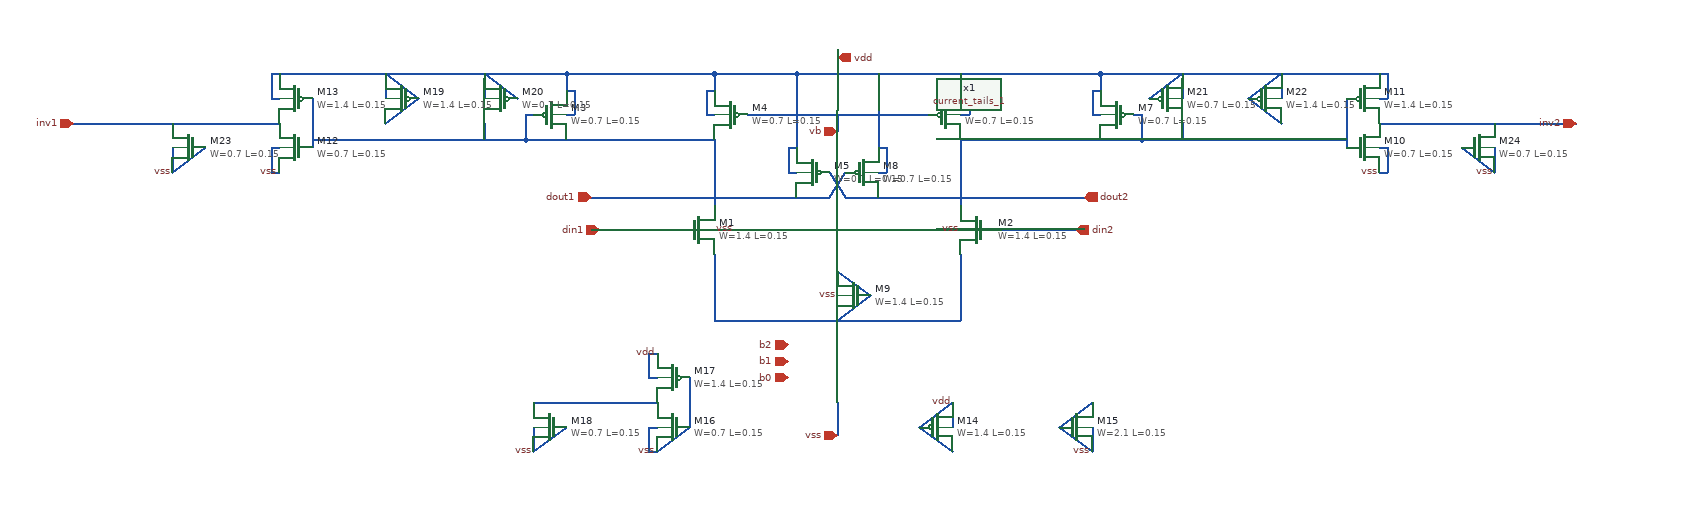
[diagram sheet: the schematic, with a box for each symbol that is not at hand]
v {xschem version=3.1.0 file_version=1.2
}
G {}
K {}
V {}
S {}
E {}
N 1120 -670 1120 -590 { lab=dout1}
N 890 -670 940 -670 { lab=dout1}
N 890 -700 890 -670 { lab=dout1}
N 890 -700 900 -700 { lab=dout1}
N 940 -750 940 -730 { lab=vdd}
N 1120 -750 1120 -730 { lab=vdd}
N 1140 -750 1220 -750 { lab=vdd}
N 1220 -750 1220 -660 { lab=vdd}
N 1210 -630 1220 -630 { lab=vdd}
N 1210 -660 1210 -630 { lab=vdd}
N 1210 -660 1220 -660 { lab=vdd}
N 1140 -600 1220 -600 { lab=dout1}
N 1420 -670 1420 -590 { lab=dout2}
N 1590 -670 1640 -670 { lab=dout2}
N 1640 -700 1640 -670 { lab=dout2}
N 1630 -700 1640 -700 { lab=dout2}
N 1590 -750 1590 -730 { lab=vdd}
N 1220 -750 1480 -750 { lab=vdd}
N 1420 -750 1420 -730 { lab=vdd}
N 1320 -600 1400 -600 { lab=dout2}
N 1320 -750 1320 -660 { lab=vdd}
N 1320 -630 1330 -630 { lab=vdd}
N 1330 -660 1330 -630 { lab=vdd}
N 1320 -660 1330 -660 { lab=vdd}
N 1110 -700 1120 -700 { lab=vdd}
N 1110 -730 1110 -700 { lab=vdd}
N 1110 -730 1120 -730 { lab=vdd}
N 1420 -700 1430 -700 { lab=vdd}
N 1430 -730 1430 -700 { lab=vdd}
N 1420 -730 1430 -730 { lab=vdd}
N 1580 -700 1590 -700 { lab=vdd}
N 1580 -730 1580 -700 { lab=vdd}
N 1580 -730 1590 -730 { lab=vdd}
N 940 -700 950 -700 { lab=vdd}
N 950 -730 950 -700 { lab=vdd}
N 940 -730 950 -730 { lab=vdd}
N 970 -560 1080 -560 { lab=din1}
N 1460 -560 1570 -560 { lab=din2}
N 1420 -600 1570 -600 { lab=dout2}
N 970 -600 1120 -600 { lab=dout1}
N 1180 -700 1360 -700 { lab=vb}
N 1270 -700 1270 -680 { lab=vb}
N 1270 -780 1270 -750 {
lab=vdd}
N 1570 -750 1590 -750 {
lab=vdd}
N 940 -750 970 -750 {
lab=vdd}
N 1400 -600 1420 -600 {
lab=dout2}
N 1360 -700 1380 -700 {
lab=vb}
N 1120 -600 1140 -600 {
lab=dout1}
N 1160 -700 1180 -700 {
lab=vb}
N 1120 -750 1140 -750 {
lab=vdd}
N 970 -750 1120 -750 {
lab=vdd}
N 1480 -750 1570 -750 {
lab=vdd}
N 1420 -670 1590 -670 {
lab=dout2}
N 940 -670 1120 -670 {
lab=dout1}
N 1220 -600 1260 -600 {
lab=dout1}
N 1260 -600 1280 -630 {
lab=dout1}
N 1260 -630 1280 -600 {
lab=dout2}
N 1280 -600 1320 -600 {
lab=dout2}
N 1120 -530 1120 -450 {
lab=#net1}
N 1120 -450 1420 -450 {
lab=#net1}
N 1420 -530 1420 -450 {
lab=#net1}
N 1270 -510 1310 -480 {
lab=#net1}
N 1270 -450 1310 -480 {
lab=#net1}
N 1930 -720 1940 -720 {
lab=vdd}
N 1940 -750 1940 -720 {
lab=vdd}
N 1930 -750 1940 -750 {
lab=vdd}
N 1930 -630 1940 -630 {
lab=vss}
N 1940 -660 1940 -630 {
lab=vss}
N 1930 -660 1940 -660 {
lab=vss}
N 580 -630 590 -630 {
lab=vss}
N 580 -660 580 -630 {
lab=vss}
N 580 -660 590 -660 {
lab=vss}
N 580 -720 590 -720 {
lab=vdd}
N 580 -750 580 -720 {
lab=vdd}
N 580 -750 590 -750 {
lab=vdd}
N 1890 -720 1890 -660 {
lab=dout2}
N 630 -720 630 -660 {
lab=dout1}
N 1370 -320 1410 -290 {
lab=vdd}
N 1370 -320 1410 -350 {
lab=vdd}
N 1410 -350 1410 -320 {
lab=vdd}
N 1540 -320 1580 -290 {
lab=vss}
N 1540 -320 1580 -350 {
lab=vss}
N 1580 -320 1580 -290 {
lab=vss}
N 1040 -290 1050 -290 {
lab=vss}
N 1040 -320 1040 -290 {
lab=vss}
N 1040 -320 1050 -320 {
lab=vss}
N 1040 -380 1050 -380 {
lab=vdd}
N 1040 -410 1040 -380 {
lab=vdd}
N 1040 -410 1050 -410 {
lab=vdd}
N 1090 -380 1090 -320 {
lab=vss}
N 1050 -290 1090 -320 {
lab=vss}
N 750 -670 890 -670 {
lab=dout1}
N 710 -750 940 -750 {
lab=vdd}
N 1590 -750 1820 -750 {
lab=vdd}
N 1640 -670 1780 -670 {
lab=dout2}
N 1690 -750 1690 -720 {
lab=vdd}
N 1650 -720 1690 -750 {
lab=vdd}
N 1690 -690 1690 -670 {
lab=dout2}
N 720 -750 720 -720 {
lab=vdd}
N 720 -750 760 -720 {
lab=vdd}
N 1930 -690 2030 -690 {
lab=inv1}
N 500 -690 590 -690 {
lab=inv1}
N 1780 -670 1890 -670 {
lab=dout2}
N 1770 -720 1810 -690 {
lab=vdd}
N 1770 -720 1810 -750 {
lab=vdd}
N 1810 -750 1810 -720 {
lab=vdd}
N 1820 -750 1930 -750 {
lab=vdd}
N 720 -690 760 -720 {
lab=vdd}
N 2030 -690 2170 -690 {
lab=inv1}
N 340 -690 500 -690 {
lab=inv1}
N 460 -630 500 -660 {
lab=vss}
N 460 -660 460 -630 {
lab=vss}
N 900 -350 1050 -350 {
lab=#net2}
N 900 -290 940 -320 {
lab=vss}
N 900 -320 900 -290 {
lab=vss}
N 630 -670 750 -670 {
lab=dout1}
N 590 -750 710 -750 {
lab=vdd}
N 840 -690 840 -670 {
lab=dout1}
N 840 -750 880 -720 {
lab=vdd}
N 840 -750 840 -720 {
lab=vdd}
N 2030 -660 2070 -630 {
lab=vss}
N 2070 -660 2070 -630 {
lab=vss}
N 1270 -350 1270 -310 {
lab=vss}
C {sky130_fd_pr/pfet_01v8.sym} 1240 -630 0 1 {name=M5
L=0.15
W=0.7
nf=1
mult=1
ad="'int((nf+1)/2) * W/nf * 0.29'" 
pd="'2*int((nf+1)/2) * (W/nf + 0.29)'"
as="'int((nf+2)/2) * W/nf * 0.29'" 
ps="'2*int((nf+2)/2) * (W/nf + 0.29)'"
nrd="'0.29 / W'" nrs="'0.29 / W'"
sa=0 sb=0 sd=0
model=pfet_01v8
spiceprefix=X
}
C {sky130_fd_pr/pfet_01v8.sym} 1300 -630 0 0 {name=M8
L=0.15
W=0.7
nf=1
mult=1
ad="'int((nf+1)/2) * W/nf * 0.29'" 
pd="'2*int((nf+1)/2) * (W/nf + 0.29)'"
as="'int((nf+2)/2) * W/nf * 0.29'" 
ps="'2*int((nf+2)/2) * (W/nf + 0.29)'"
nrd="'0.29 / W'" nrs="'0.29 / W'"
sa=0 sb=0 sd=0
model=pfet_01v8
spiceprefix=X
}
C {sky130_fd_pr/pfet_01v8.sym} 920 -700 0 0 {name=M3
L=0.15
W=0.7
nf=1
mult=1
ad="'int((nf+1)/2) * W/nf * 0.29'" 
pd="'2*int((nf+1)/2) * (W/nf + 0.29)'"
as="'int((nf+2)/2) * W/nf * 0.29'" 
ps="'2*int((nf+2)/2) * (W/nf + 0.29)'"
nrd="'0.29 / W'" nrs="'0.29 / W'"
sa=0 sb=0 sd=0
model=pfet_01v8
spiceprefix=X
}
C {sky130_fd_pr/pfet_01v8.sym} 1140 -700 0 1 {name=M4
L=0.15
W=0.7
nf=1
mult=1
ad="'int((nf+1)/2) * W/nf * 0.29'" 
pd="'2*int((nf+1)/2) * (W/nf + 0.29)'"
as="'int((nf+2)/2) * W/nf * 0.29'" 
ps="'2*int((nf+2)/2) * (W/nf + 0.29)'"
nrd="'0.29 / W'" nrs="'0.29 / W'"
sa=0 sb=0 sd=0
model=pfet_01v8
spiceprefix=X
}
C {sky130_fd_pr/pfet_01v8.sym} 1400 -700 0 0 {name=M6
L=0.15
W=0.7
nf=1
mult=1
ad="'int((nf+1)/2) * W/nf * 0.29'" 
pd="'2*int((nf+1)/2) * (W/nf + 0.29)'"
as="'int((nf+2)/2) * W/nf * 0.29'" 
ps="'2*int((nf+2)/2) * (W/nf + 0.29)'"
nrd="'0.29 / W'" nrs="'0.29 / W'"
sa=0 sb=0 sd=0
model=pfet_01v8
spiceprefix=X
}
C {sky130_fd_pr/pfet_01v8.sym} 1610 -700 0 1 {name=M7
L=0.15
W=0.7
nf=1
mult=1
ad="'int((nf+1)/2) * W/nf * 0.29'" 
pd="'2*int((nf+1)/2) * (W/nf + 0.29)'"
as="'int((nf+2)/2) * W/nf * 0.29'" 
ps="'2*int((nf+2)/2) * (W/nf + 0.29)'"
nrd="'0.29 / W'" nrs="'0.29 / W'"
sa=0 sb=0 sd=0
model=pfet_01v8
spiceprefix=X
}
C {devices/iopin.sym} 1270 -770 1 1 {name=p1 lab=vdd}
C {devices/iopin.sym} 1270 -310 1 0 {name=p2 lab=vss}
C {devices/iopin.sym} 1270 -680 1 0 {name=p3 lab=vb}
C {devices/iopin.sym} 980 -560 2 0 {name=p4 lab=din1}
C {devices/iopin.sym} 1560 -560 2 1 {name=p5 lab=din2}
C {devices/iopin.sym} 1570 -600 2 1 {name=p6 lab=dout2}
C {devices/iopin.sym} 970 -600 2 0 {name=p7 lab=dout1}
C {sky130_fd_pr/nfet_01v8_lvt.sym} 1100 -560 0 0 {name=M1
L=0.15
W=1.4
nf=2
mult=1
ad="'int((nf+1)/2) * W/nf * 0.29'" 
pd="'2*int((nf+1)/2) * (W/nf + 0.29)'"
as="'int((nf+2)/2) * W/nf * 0.29'" 
ps="'2*int((nf+2)/2) * (W/nf + 0.29)'"
nrd="'0.29 / W'" nrs="'0.29 / W'"
sa=0 sb=0 sd=0
model=nfet_01v8_lvt
spiceprefix=X
}
C {sky130_fd_pr/nfet_01v8_lvt.sym} 1440 -560 0 1 {name=M2
L=0.15
W=1.4
nf=2
mult=1
ad="'int((nf+1)/2) * W/nf * 0.29'" 
pd="'2*int((nf+1)/2) * (W/nf + 0.29)'"
as="'int((nf+2)/2) * W/nf * 0.29'" 
ps="'2*int((nf+2)/2) * (W/nf + 0.29)'"
nrd="'0.29 / W'" nrs="'0.29 / W'"
sa=0 sb=0 sd=0
model=nfet_01v8_lvt
spiceprefix=X
}
C {devices/iopin.sym} 1210 -420 2 0 {name=p8 lab=b2}
C {devices/iopin.sym} 1210 -400 2 0 {name=p9 lab=b1}
C {devices/iopin.sym} 1210 -380 2 0 {name=p10 lab=b0}
C {sky130_fd_pr/nfet_01v8_lvt.sym} 1290 -480 0 1 {name=M9
L=0.15
W=1.4
nf=2
mult=1
ad="'int((nf+1)/2) * W/nf * 0.29'" 
pd="'2*int((nf+1)/2) * (W/nf + 0.29)'"
as="'int((nf+2)/2) * W/nf * 0.29'" 
ps="'2*int((nf+2)/2) * (W/nf + 0.29)'"
nrd="'0.29 / W'" nrs="'0.29 / W'"
sa=0 sb=0 sd=0
model=nfet_01v8_lvt
spiceprefix=X
}
C {current_tails_1.sym} 1360 -400 0 0 {name=x1}
C {sky130_fd_pr/nfet_01v8.sym} 1910 -660 0 0 {name=M10
L=0.15
W=0.7
nf=1 
mult=1
ad="'int((nf+1)/2) * W/nf * 0.29'" 
pd="'2*int((nf+1)/2) * (W/nf + 0.29)'"
as="'int((nf+2)/2) * W/nf * 0.29'" 
ps="'2*int((nf+2)/2) * (W/nf + 0.29)'"
nrd="'0.29 / W'" nrs="'0.29 / W'"
sa=0 sb=0 sd=0
model=nfet_01v8
spiceprefix=X
}
C {sky130_fd_pr/pfet_01v8.sym} 1910 -720 0 0 {name=M11
L=0.15
W=1.4
nf=2
mult=1
ad="'int((nf+1)/2) * W/nf * 0.29'" 
pd="'2*int((nf+1)/2) * (W/nf + 0.29)'"
as="'int((nf+2)/2) * W/nf * 0.29'" 
ps="'2*int((nf+2)/2) * (W/nf + 0.29)'"
nrd="'0.29 / W'" nrs="'0.29 / W'"
sa=0 sb=0 sd=0
model=pfet_01v8
spiceprefix=X
}
C {sky130_fd_pr/nfet_01v8.sym} 610 -660 0 1 {name=M12
L=0.15
W=0.7
nf=1 
mult=1
ad="'int((nf+1)/2) * W/nf * 0.29'" 
pd="'2*int((nf+1)/2) * (W/nf + 0.29)'"
as="'int((nf+2)/2) * W/nf * 0.29'" 
ps="'2*int((nf+2)/2) * (W/nf + 0.29)'"
nrd="'0.29 / W'" nrs="'0.29 / W'"
sa=0 sb=0 sd=0
model=nfet_01v8
spiceprefix=X
}
C {sky130_fd_pr/pfet_01v8.sym} 610 -720 0 1 {name=M13
L=0.15
W=1.4
nf=2
mult=1
ad="'int((nf+1)/2) * W/nf * 0.29'" 
pd="'2*int((nf+1)/2) * (W/nf + 0.29)'"
as="'int((nf+2)/2) * W/nf * 0.29'" 
ps="'2*int((nf+2)/2) * (W/nf + 0.29)'"
nrd="'0.29 / W'" nrs="'0.29 / W'"
sa=0 sb=0 sd=0
model=pfet_01v8
spiceprefix=X
}
C {devices/lab_pin.sym} 590 -630 3 0 {name=p11 sig_type=std_logic lab=vss}
C {devices/lab_pin.sym} 1930 -630 3 0 {name=p12 sig_type=std_logic lab=vss}
C {sky130_fd_pr/pfet_01v8.sym} 1390 -320 0 0 {name=M14
L=0.15
W=1.4
nf=2
mult=1
ad="'int((nf+1)/2) * W/nf * 0.29'" 
pd="'2*int((nf+1)/2) * (W/nf + 0.29)'"
as="'int((nf+2)/2) * W/nf * 0.29'" 
ps="'2*int((nf+2)/2) * (W/nf + 0.29)'"
nrd="'0.29 / W'" nrs="'0.29 / W'"
sa=0 sb=0 sd=0
model=pfet_01v8
spiceprefix=X
}
C {sky130_fd_pr/nfet_01v8.sym} 1560 -320 0 0 {name=M15
L=0.15
W=2.1
nf=3
mult=1
ad="'int((nf+1)/2) * W/nf * 0.29'" 
pd="'2*int((nf+1)/2) * (W/nf + 0.29)'"
as="'int((nf+2)/2) * W/nf * 0.29'" 
ps="'2*int((nf+2)/2) * (W/nf + 0.29)'"
nrd="'0.29 / W'" nrs="'0.29 / W'"
sa=0 sb=0 sd=0
model=nfet_01v8
spiceprefix=X
}
C {devices/lab_pin.sym} 1580 -290 3 0 {name=p13 sig_type=std_logic lab=vss}
C {devices/lab_pin.sym} 1410 -350 1 0 {name=p14 sig_type=std_logic lab=vdd}
C {sky130_fd_pr/nfet_01v8.sym} 1070 -320 0 1 {name=M16
L=0.15
W=0.7
nf=1 
mult=1
ad="'int((nf+1)/2) * W/nf * 0.29'" 
pd="'2*int((nf+1)/2) * (W/nf + 0.29)'"
as="'int((nf+2)/2) * W/nf * 0.29'" 
ps="'2*int((nf+2)/2) * (W/nf + 0.29)'"
nrd="'0.29 / W'" nrs="'0.29 / W'"
sa=0 sb=0 sd=0
model=nfet_01v8
spiceprefix=X
}
C {sky130_fd_pr/pfet_01v8.sym} 1070 -380 0 1 {name=M17
L=0.15
W=1.4
nf=2
mult=1
ad="'int((nf+1)/2) * W/nf * 0.29'" 
pd="'2*int((nf+1)/2) * (W/nf + 0.29)'"
as="'int((nf+2)/2) * W/nf * 0.29'" 
ps="'2*int((nf+2)/2) * (W/nf + 0.29)'"
nrd="'0.29 / W'" nrs="'0.29 / W'"
sa=0 sb=0 sd=0
model=pfet_01v8
spiceprefix=X
}
C {devices/lab_pin.sym} 1050 -290 3 0 {name=p15 sig_type=std_logic lab=vss}
C {sky130_fd_pr/pfet_01v8.sym} 1670 -720 0 0 {name=M21
L=0.15
W=0.7
nf=1
mult=1
ad="'int((nf+1)/2) * W/nf * 0.29'" 
pd="'2*int((nf+1)/2) * (W/nf + 0.29)'"
as="'int((nf+2)/2) * W/nf * 0.29'" 
ps="'2*int((nf+2)/2) * (W/nf + 0.29)'"
nrd="'0.29 / W'" nrs="'0.29 / W'"
sa=0 sb=0 sd=0
model=pfet_01v8
spiceprefix=X
}
C {sky130_fd_pr/pfet_01v8.sym} 860 -720 0 1 {name=M20
L=0.15
W=0.7
nf=1
mult=1
ad="'int((nf+1)/2) * W/nf * 0.29'" 
pd="'2*int((nf+1)/2) * (W/nf + 0.29)'"
as="'int((nf+2)/2) * W/nf * 0.29'" 
ps="'2*int((nf+2)/2) * (W/nf + 0.29)'"
nrd="'0.29 / W'" nrs="'0.29 / W'"
sa=0 sb=0 sd=0
model=pfet_01v8
spiceprefix=X
}
C {devices/lab_pin.sym} 1050 -410 1 0 {name=p18 sig_type=std_logic lab=vdd}
C {sky130_fd_pr/pfet_01v8.sym} 1790 -720 0 0 {name=M22
L=0.15
W=1.4
nf=2
mult=1
ad="'int((nf+1)/2) * W/nf * 0.29'" 
pd="'2*int((nf+1)/2) * (W/nf + 0.29)'"
as="'int((nf+2)/2) * W/nf * 0.29'" 
ps="'2*int((nf+2)/2) * (W/nf + 0.29)'"
nrd="'0.29 / W'" nrs="'0.29 / W'"
sa=0 sb=0 sd=0
model=pfet_01v8
spiceprefix=X
}
C {devices/lab_pin.sym} 460 -630 3 0 {name=p19 sig_type=std_logic lab=vss}
C {sky130_fd_pr/nfet_01v8.sym} 920 -320 0 1 {name=M18
L=0.15
W=0.7
nf=1
mult=1
ad="'int((nf+1)/2) * W/nf * 0.29'" 
pd="'2*int((nf+1)/2) * (W/nf + 0.29)'"
as="'int((nf+2)/2) * W/nf * 0.29'" 
ps="'2*int((nf+2)/2) * (W/nf + 0.29)'"
nrd="'0.29 / W'" nrs="'0.29 / W'"
sa=0 sb=0 sd=0
model=nfet_01v8
spiceprefix=X
}
C {devices/lab_pin.sym} 900 -290 3 0 {name=p16 sig_type=std_logic lab=vss}
C {sky130_fd_pr/pfet_01v8.sym} 740 -720 0 1 {name=M19
L=0.15
W=1.4
nf=2
mult=1
ad="'int((nf+1)/2) * W/nf * 0.29'" 
pd="'2*int((nf+1)/2) * (W/nf + 0.29)'"
as="'int((nf+2)/2) * W/nf * 0.29'" 
ps="'2*int((nf+2)/2) * (W/nf + 0.29)'"
nrd="'0.29 / W'" nrs="'0.29 / W'"
sa=0 sb=0 sd=0
model=pfet_01v8
spiceprefix=X
}
C {devices/lab_pin.sym} 2070 -630 3 0 {name=p17 sig_type=std_logic lab=vss}
C {sky130_fd_pr/nfet_01v8.sym} 480 -660 0 1 {name=M23
L=0.15
W=0.7
nf=1
mult=1
ad="'int((nf+1)/2) * W/nf * 0.29'" 
pd="'2*int((nf+1)/2) * (W/nf + 0.29)'"
as="'int((nf+2)/2) * W/nf * 0.29'" 
ps="'2*int((nf+2)/2) * (W/nf + 0.29)'"
nrd="'0.29 / W'" nrs="'0.29 / W'"
sa=0 sb=0 sd=0
model=nfet_01v8
spiceprefix=X
}
C {sky130_fd_pr/nfet_01v8.sym} 2050 -660 0 0 {name=M24
L=0.15
W=0.7
nf=1
mult=1
ad="'int((nf+1)/2) * W/nf * 0.29'" 
pd="'2*int((nf+1)/2) * (W/nf + 0.29)'"
as="'int((nf+2)/2) * W/nf * 0.29'" 
ps="'2*int((nf+2)/2) * (W/nf + 0.29)'"
nrd="'0.29 / W'" nrs="'0.29 / W'"
sa=0 sb=0 sd=0
model=nfet_01v8
spiceprefix=X
}
C {devices/lab_pin.sym} 1420 -560 0 0 {name=p20 sig_type=std_logic lab=vss}
C {devices/lab_pin.sym} 1270 -480 0 0 {name=p21 sig_type=std_logic lab=vss}
C {devices/lab_pin.sym} 1120 -560 0 1 {name=p22 sig_type=std_logic lab=vss}
C {devices/iopin.sym} 340 -690 3 0 {name=p23 lab=inv1}
C {devices/iopin.sym} 2170 -690 3 0 {name=p25 lab=inv2}
